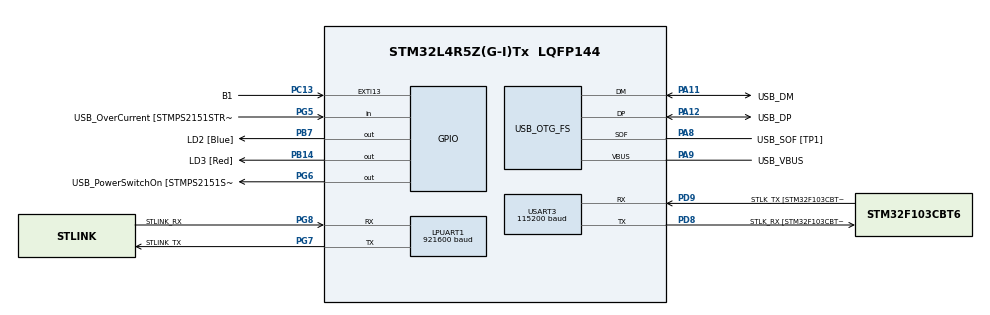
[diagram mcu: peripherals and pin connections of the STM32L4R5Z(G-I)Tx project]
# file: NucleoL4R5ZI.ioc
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Dma.LPUART1_RX.0.Direction=DMA_PERIPH_TO_MEMORY
Dma.LPUART1_RX.0.EventEnable=DISABLE
Dma.LPUART1_RX.0.Instance=DMA1_Channel1
Dma.LPUART1_RX.0.MemDataAlignment=DMA_MDATAALIGN_BYTE
Dma.LPUART1_RX.0.MemInc=DMA_MINC_ENABLE
Dma.LPUART1_RX.0.Mode=DMA_NORMAL
Dma.LPUART1_RX.0.PeriphDataAlignment=DMA_PDATAALIGN_BYTE
Dma.LPUART1_RX.0.PeriphInc=DMA_PINC_DISABLE
Dma.LPUART1_RX.0.Polarity=HAL_DMAMUX_REQUEST_GEN_RISING
Dma.LPUART1_RX.0.Priority=DMA_PRIORITY_MEDIUM
Dma.LPUART1_RX.0.RequestNumber=1
Dma.LPUART1_RX.0.SignalID=NONE
Dma.LPUART1_RX.0.SyncEnable=DISABLE
Dma.LPUART1_RX.0.SyncPolarity=HAL_DMAMUX_SYNC_NO_EVENT
Dma.LPUART1_RX.0.SyncRequestNumber=1
Dma.LPUART1_RX.0.SyncSignalID=NONE
Dma.Request0=LPUART1_RX
LPUART1.BaudRate=921600
LPUART1.OneBitSampling=UART_ONE_BIT_SAMPLE_DISABLE
LPUART1.WordLength=UART_WORDLENGTH_8B
Mcu.Family=STM32L4
Mcu.Name=STM32L4R5Z(G-I)Tx
Mcu.Package=LQFP144
NVIC.DMA1_Channel1_IRQn=true\:0\:0\:false\:false\:true\:false\:true\:true
NVIC.LPUART1_IRQn=true\:0\:0\:false\:false\:true\:true\:true\:true
NVIC.PriorityGroup=NVIC_PRIORITYGROUP_4
PA10.GPIO_Label=USB_ID
PA10.Signal=USB_OTG_FS_ID
PA11.GPIO_Label=USB_DM
PA11.Mode=Device_Only
PA11.Signal=USB_OTG_FS_DM
PA12.GPIO_Label=USB_DP
PA12.Mode=Device_Only
PA12.Signal=USB_OTG_FS_DP
PA13\ (JTMS/SWDIO).GPIO_Label=TMS
PA13\ (JTMS/SWDIO).Mode=Trace_Asynchronous_SW
PA13\ (JTMS/SWDIO).Signal=SYS_JTMS-SWDIO
PA14\ (JTCK/SWCLK).GPIO_Label=TCK
PA14\ (JTCK/SWCLK).Mode=Trace_Asynchronous_SW
PA14\ (JTCK/SWCLK).Signal=SYS_JTCK-SWCLK
PA8.GPIO_Label=USB_SOF [TP1]
PA8.Mode=Activate_SOF_FS
PA8.Signal=USB_OTG_FS_SOF
PA9.GPIO_Label=USB_VBUS
PA9.Mode=Activate_VBUS
PA9.Signal=USB_OTG_FS_VBUS
PB14.GPIO_Label=LD3 [Red]
PB14.Signal=GPIO_Output
PB3\ (JTDO/TRACESWO).GPIO_Label=SWO
PB3\ (JTDO/TRACESWO).Mode=Trace_Asynchronous_SW
PB3\ (JTDO/TRACESWO).Signal=SYS_JTDO-SWO
PB7.GPIO_Label=LD2 [Blue]
PB7.Signal=GPIO_Output
PC13.GPIO_Label=B1
PC13.Signal=GPXTI13
PC14-OSC32_IN\ (PC14).Mode=LSE-External-Oscillator
PC14-OSC32_IN\ (PC14).Signal=RCC_OSC32_IN
PC15-OSC32_OUT\ (PC15).Mode=LSE-External-Oscillator
PC15-OSC32_OUT\ (PC15).Signal=RCC_OSC32_OUT
PD8.GPIO_Label=STLK_RX [STM32F103CBT6_PA3]
PD8.Mode=Asynchronous
PD8.Signal=USART3_TX
PD9.GPIO_Label=STLK_TX [STM32F103CBT6_PA2]
PD9.Mode=Asynchronous
PD9.Signal=USART3_RX
PG5.GPIO_Label=USB_OverCurrent [STMPS2151STR_FAULT]
PG5.Signal=GPIO_Input
PG6.GPIO_Label=USB_PowerSwitchOn [STMPS2151STR_EN]
PG6.Signal=GPIO_Output
PG7.GPIO_Label=STLINK_TX
PG7.Mode=Asynchronous
PG7.Signal=LPUART1_TX
PG8.GPIO_Label=STLINK_RX
PG8.Mode=Asynchronous
PG8.Signal=LPUART1_RX
PH0-OSC_IN\ (PH0).Signal=RCC_OSC_IN
PH1-OSC_OUT\ (PH1).Signal=RCC_OSC_OUT
ProjectManager.HeapSize=0x200
ProjectManager.StackSize=0x400
ProjectManager.TargetToolchain=Makefile
RCC.48MHZClocksFreq_Value=24000000
RCC.ADCFreq_Value=96000000
RCC.AHBFreq_Value=120000000
RCC.APB1CLKDivider=RCC_HCLK_DIV2
RCC.APB1Freq_Value=60000000
RCC.APB1TimFreq_Value=120000000
RCC.APB2Freq_Value=120000000
RCC.APB2TimFreq_Value=120000000
RCC.CK48CLockSelection=RCC_USBCLKSOURCE_HSI48
RCC.CortexFreq_Value=120000000
RCC.HCLKFreq_Value=120000000
RCC.HSE_VALUE=8000000
RCC.HSI48_VALUE=48000000
RCC.HSI_VALUE=16000000
RCC.MSI_VALUE=4000000
RCC.PLLM1=2
RCC.PLLMUL=RCC_PLL_MUL9
RCC.PLLN=30
RCC.PLLSAI1N=12
RCC.PLLSourceVirtual=RCC_PLLSOURCE_HSI
RCC.PRESCALERUSB=RCC_USBCLKSOURCE_PLL_DIV1_5
RCC.SYSCLKFreq_VALUE=120000000
RCC.SYSCLKSource=RCC_SYSCLKSOURCE_PLLCLK
RCC.SYSCLKSourceVirtual=RCC_SYSCLKSOURCE_PLLCLK
RCC.USBFreq_Value=48000000
RCC.VCOOutputFreq_Value=240000000
USART3.BaudRate=115200
USART3.VirtualMode-Asynchronous=VM_ASYNC
USB_OTG_FS.VirtualMode=Device_Only
board=NUCLEO-L4R5ZI

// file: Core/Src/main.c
/* USER CODE BEGIN Header */
/**
  ******************************************************************************
  * @file           : main.c
  * @brief          : Main program body
  ******************************************************************************
  * @attention
  *
  * Copyright (c) 2026 STMicroelectronics.
  * All rights reserved.
  *
  * This software is licensed under terms that can be found in the LICENSE file
  * in the root directory of this software component.
  * If no LICENSE file comes with this software, it is provided AS-IS.
  *
  ******************************************************************************
  */
/* USER CODE END Header */
#include "main.h"

/* USER CODE BEGIN Includes */
#include <stdint.h>
#include <stdio.h>

#include "NeuralNetwork.h"
/* USER CODE END Includes */

/* USER CODE BEGIN PD */
#define MAX_READ_SIZE 16384 // Absolute max is 65535 due to HAL_UART_Receive_DMA size being uint16_t
/* USER CODE END PD */

UART_HandleTypeDef hlpuart1;
UART_HandleTypeDef huart3;
DMA_HandleTypeDef hdma_lpuart1_rx;

PCD_HandleTypeDef hpcd_USB_OTG_FS;

/* USER CODE BEGIN PV */
volatile static char receive_buff[MAX_READ_SIZE] = {'\0'};                //Define the receive array
volatile uint16_t receive_buff_cnt = 0;
static char send_msg[32] = "READY\r\n";
/* USER CODE END PV */

void SystemClock_Config(void);
static void MX_GPIO_Init(void);
static void MX_DMA_Init(void);
static void MX_LPUART1_UART_Init(void);
static void MX_USART3_UART_Init(void);
static void MX_USB_OTG_FS_PCD_Init(void);

/* USER CODE BEGIN 0 */
void RxEventCallback(UART_HandleTypeDef *huart, uint16_t Pos) {
  if(huart->Instance == LPUART1) { //Determine whether it is serial port 2
    uint16_t max_read = MAX_READ_SIZE - receive_buff_cnt;

    //Calculate the length of the received data
    //uint16_t data_length  = max_read - __HAL_DMA_GET_COUNTER(&hdma_usart2_rx);
    uint16_t data_length = Pos;

    receive_buff_cnt += data_length;

    if (receive_buff[receive_buff_cnt - 1] != '\n') {
      max_read -= data_length;
      //Restart to start DMA transmission of MAX_READ_SIZE bytes of data at a time
      HAL_UARTEx_ReceiveToIdle_DMA(&hlpuart1, (uint8_t*)(receive_buff + receive_buff_cnt), max_read);
    }
  }
}

/**
  * @brief  Function called to read the current micro second
  * @param  None
  * @retval None
  */
uint32_t getCurrentMicros(void)
{
  uint32_t m0 = HAL_GetTick();
  __IO uint32_t u0 = SysTick->VAL;
  uint32_t m1 = HAL_GetTick();
  __IO uint32_t u1 = SysTick->VAL;
  const uint32_t tms = SysTick->LOAD + 1;

  if (m1 != m0) {
    return (m1 * 1000 + ((tms - u1) * 1000) / tms);
  } else {
    return (m0 * 1000 + ((tms - u0) * 1000) / tms);
  }
}
/* USER CODE END 0 */

int main(void)
{

  /* MCU Configuration--------------------------------------------------------*/

  /* Reset of all peripherals, Initializes the Flash interface and the Systick. */
  HAL_Init();

  /* Configure the system clock */
  SystemClock_Config();

  /* Initialize all configured peripherals */
  MX_GPIO_Init();
  MX_DMA_Init();
  MX_LPUART1_UART_Init();
  MX_USART3_UART_Init();
  MX_USB_OTG_FS_PCD_Init();
  /* USER CODE BEGIN 2 */
  HAL_UART_RegisterRxEventCallback(&hlpuart1, RxEventCallback);
  HAL_UARTEx_ReceiveToIdle_DMA(&hlpuart1, (uint8_t*)receive_buff, MAX_READ_SIZE);
  HAL_UART_Transmit(&hlpuart1, (unsigned char *)send_msg, 7, 0x200); // Send READY
  /* USER CODE END 2 */

  /* Infinite loop */
  /* USER CODE BEGIN WHILE */
  while (1)
  {
    if (receive_buff_cnt > 0 && receive_buff[receive_buff_cnt - 1] == '\n') {
      float *inputs = serialBufToFloats(receive_buff, receive_buff_cnt);
      size_t len = snprintf(send_msg, 32, "%d\r\n", receive_buff_cnt);
      receive_buff_cnt = 0;
      HAL_UARTEx_ReceiveToIdle_DMA(&hlpuart1, (uint8_t*)receive_buff, MAX_READ_SIZE);

      HAL_UART_Transmit(&hlpuart1, (unsigned char *)send_msg, len, 0x200);

      uint32_t start = getCurrentMicros();
      struct NNResult res = neuralNetworkInfer(inputs);
      uint32_t stop = getCurrentMicros();

      len = snprintf(send_msg, 32, "%d,%d,%f,%lu\r\n", res.inference_count, res.label, (double)res.dist, stop - start);
      HAL_UART_Transmit(&hlpuart1, (unsigned char *)send_msg, len, 0x200);
    }
    /* USER CODE END WHILE */

  }
}

void SystemClock_Config(void)
{
  RCC_OscInitTypeDef RCC_OscInitStruct = {0};
  RCC_ClkInitTypeDef RCC_ClkInitStruct = {0};

  /** Configure the main internal regulator output voltage
  */
#ifdef CORE_CLOCK_48MHZ
  if (HAL_PWREx_ControlVoltageScaling(PWR_REGULATOR_VOLTAGE_SCALE1) != HAL_OK)
#else
  if (HAL_PWREx_ControlVoltageScaling(PWR_REGULATOR_VOLTAGE_SCALE1_BOOST) != HAL_OK)
#endif
  {
    Error_Handler();
  }

  /** Initializes the RCC Oscillators according to the specified parameters
  * in the RCC_OscInitTypeDef structure.
  */
  RCC_OscInitStruct.OscillatorType = RCC_OSCILLATORTYPE_HSI48|RCC_OSCILLATORTYPE_HSI;
  RCC_OscInitStruct.HSIState = RCC_HSI_ON;
  RCC_OscInitStruct.HSI48State = RCC_HSI48_ON;
  RCC_OscInitStruct.HSICalibrationValue = RCC_HSICALIBRATION_DEFAULT;
  RCC_OscInitStruct.PLL.PLLState = RCC_PLL_ON;
  RCC_OscInitStruct.PLL.PLLSource = RCC_PLLSOURCE_HSI;
#ifdef CORE_CLOCK_48MHZ
  RCC_OscInitStruct.PLL.PLLM = 1;
  RCC_OscInitStruct.PLL.PLLN = 12;
#else
  RCC_OscInitStruct.PLL.PLLM = 2;
  RCC_OscInitStruct.PLL.PLLN = 30;
#endif
  RCC_OscInitStruct.PLL.PLLP = RCC_PLLP_DIV2;
  RCC_OscInitStruct.PLL.PLLQ = RCC_PLLQ_DIV2;
  RCC_OscInitStruct.PLL.PLLR = RCC_PLLR_DIV2;
  if (HAL_RCC_OscConfig(&RCC_OscInitStruct) != HAL_OK)
  {
    Error_Handler();
  }

  /** Initializes the CPU, AHB and APB buses clocks
  */
  RCC_ClkInitStruct.ClockType = RCC_CLOCKTYPE_HCLK|RCC_CLOCKTYPE_SYSCLK
                              |RCC_CLOCKTYPE_PCLK1|RCC_CLOCKTYPE_PCLK2;
  RCC_ClkInitStruct.SYSCLKSource = RCC_SYSCLKSOURCE_PLLCLK;
#ifdef CORE_CLOCK_48MHZ
  RCC_ClkInitStruct.AHBCLKDivider = RCC_SYSCLK_DIV2;
#else
  RCC_ClkInitStruct.AHBCLKDivider = RCC_SYSCLK_DIV1;
#endif
  RCC_ClkInitStruct.APB1CLKDivider = RCC_HCLK_DIV2;
  RCC_ClkInitStruct.APB2CLKDivider = RCC_HCLK_DIV1;

#ifdef CORE_CLOCK_48MHZ
  if (HAL_RCC_ClockConfig(&RCC_ClkInitStruct, FLASH_LATENCY_2) != HAL_OK)
#else
  if (HAL_RCC_ClockConfig(&RCC_ClkInitStruct, FLASH_LATENCY_5) != HAL_OK)
#endif
  {
    Error_Handler();
  }
}

static void MX_LPUART1_UART_Init(void)
{

  hlpuart1.Instance = LPUART1;
  hlpuart1.Init.BaudRate = 921600;
  hlpuart1.Init.WordLength = UART_WORDLENGTH_8B;
  hlpuart1.Init.StopBits = UART_STOPBITS_1;
  hlpuart1.Init.Parity = UART_PARITY_NONE;
  hlpuart1.Init.Mode = UART_MODE_TX_RX;
  hlpuart1.Init.HwFlowCtl = UART_HWCONTROL_NONE;
  hlpuart1.Init.OneBitSampling = UART_ONE_BIT_SAMPLE_DISABLE;
  hlpuart1.Init.ClockPrescaler = UART_PRESCALER_DIV1;
  hlpuart1.AdvancedInit.AdvFeatureInit = UART_ADVFEATURE_NO_INIT;
  hlpuart1.FifoMode = UART_FIFOMODE_DISABLE;
  if (HAL_UART_Init(&hlpuart1) != HAL_OK)
  {
    Error_Handler();
  }
  if (HAL_UARTEx_SetTxFifoThreshold(&hlpuart1, UART_TXFIFO_THRESHOLD_1_8) != HAL_OK)
  {
    Error_Handler();
  }
  if (HAL_UARTEx_SetRxFifoThreshold(&hlpuart1, UART_RXFIFO_THRESHOLD_1_8) != HAL_OK)
  {
    Error_Handler();
  }
  if (HAL_UARTEx_DisableFifoMode(&hlpuart1) != HAL_OK)
  {
    Error_Handler();
  }

}

static void MX_USART3_UART_Init(void)
{

  huart3.Instance = USART3;
  huart3.Init.BaudRate = 115200;
  huart3.Init.WordLength = UART_WORDLENGTH_8B;
  huart3.Init.StopBits = UART_STOPBITS_1;
  huart3.Init.Parity = UART_PARITY_NONE;
  huart3.Init.Mode = UART_MODE_TX_RX;
  huart3.Init.HwFlowCtl = UART_HWCONTROL_NONE;
  huart3.Init.OverSampling = UART_OVERSAMPLING_16;
  huart3.Init.OneBitSampling = UART_ONE_BIT_SAMPLE_DISABLE;
  huart3.Init.ClockPrescaler = UART_PRESCALER_DIV1;
  huart3.AdvancedInit.AdvFeatureInit = UART_ADVFEATURE_NO_INIT;
  if (HAL_UART_Init(&huart3) != HAL_OK)
  {
    Error_Handler();
  }
  if (HAL_UARTEx_SetTxFifoThreshold(&huart3, UART_TXFIFO_THRESHOLD_1_8) != HAL_OK)
  {
    Error_Handler();
  }
  if (HAL_UARTEx_SetRxFifoThreshold(&huart3, UART_RXFIFO_THRESHOLD_1_8) != HAL_OK)
  {
    Error_Handler();
  }
  if (HAL_UARTEx_DisableFifoMode(&huart3) != HAL_OK)
  {
    Error_Handler();
  }

}

static void MX_USB_OTG_FS_PCD_Init(void)
{

  hpcd_USB_OTG_FS.Instance = USB_OTG_FS;
  hpcd_USB_OTG_FS.Init.dev_endpoints = 6;
  hpcd_USB_OTG_FS.Init.speed = PCD_SPEED_FULL;
  hpcd_USB_OTG_FS.Init.phy_itface = PCD_PHY_EMBEDDED;
  hpcd_USB_OTG_FS.Init.Sof_enable = ENABLE;
  hpcd_USB_OTG_FS.Init.low_power_enable = DISABLE;
  hpcd_USB_OTG_FS.Init.lpm_enable = DISABLE;
  hpcd_USB_OTG_FS.Init.battery_charging_enable = ENABLE;
  hpcd_USB_OTG_FS.Init.use_dedicated_ep1 = DISABLE;
  hpcd_USB_OTG_FS.Init.vbus_sensing_enable = ENABLE;
  if (HAL_PCD_Init(&hpcd_USB_OTG_FS) != HAL_OK)
  {
    Error_Handler();
  }

}

static void MX_DMA_Init(void)
{

  /* DMA controller clock enable */
  __HAL_RCC_DMAMUX1_CLK_ENABLE();
  __HAL_RCC_DMA1_CLK_ENABLE();

  /* DMA interrupt init */
  /* DMA1_Channel1_IRQn interrupt configuration */
  HAL_NVIC_SetPriority(DMA1_Channel1_IRQn, 0, 0);
  HAL_NVIC_EnableIRQ(DMA1_Channel1_IRQn);

}

static void MX_GPIO_Init(void)
{
  GPIO_InitTypeDef GPIO_InitStruct = {0};

  /* GPIO Ports Clock Enable */
  __HAL_RCC_GPIOC_CLK_ENABLE();
  __HAL_RCC_GPIOH_CLK_ENABLE();
  __HAL_RCC_GPIOB_CLK_ENABLE();
  __HAL_RCC_GPIOD_CLK_ENABLE();
  __HAL_RCC_GPIOG_CLK_ENABLE();
  HAL_PWREx_EnableVddIO2();
  __HAL_RCC_GPIOA_CLK_ENABLE();

  /*Configure GPIO pin Output Level */
  HAL_GPIO_WritePin(GPIOB, LD3_Pin|LD2_Pin, GPIO_PIN_RESET);

  /*Configure GPIO pin Output Level */
  HAL_GPIO_WritePin(USB_PowerSwitchOn_GPIO_Port, USB_PowerSwitchOn_Pin, GPIO_PIN_RESET);

  /*Configure GPIO pin : B1_Pin */
  GPIO_InitStruct.Pin = B1_Pin;
  GPIO_InitStruct.Mode = GPIO_MODE_IT_RISING;
  GPIO_InitStruct.Pull = GPIO_NOPULL;
  HAL_GPIO_Init(B1_GPIO_Port, &GPIO_InitStruct);

  /*Configure GPIO pins : LD3_Pin LD2_Pin */
  GPIO_InitStruct.Pin = LD3_Pin|LD2_Pin;
  GPIO_InitStruct.Mode = GPIO_MODE_OUTPUT_PP;
  GPIO_InitStruct.Pull = GPIO_NOPULL;
  GPIO_InitStruct.Speed = GPIO_SPEED_FREQ_LOW;
  HAL_GPIO_Init(GPIOB, &GPIO_InitStruct);

  /*Configure GPIO pin : USB_OverCurrent_Pin */
  GPIO_InitStruct.Pin = USB_OverCurrent_Pin;
  GPIO_InitStruct.Mode = GPIO_MODE_INPUT;
  GPIO_InitStruct.Pull = GPIO_NOPULL;
  HAL_GPIO_Init(USB_OverCurrent_GPIO_Port, &GPIO_InitStruct);

  /*Configure GPIO pin : USB_PowerSwitchOn_Pin */
  GPIO_InitStruct.Pin = USB_PowerSwitchOn_Pin;
  GPIO_InitStruct.Mode = GPIO_MODE_OUTPUT_PP;
  GPIO_InitStruct.Pull = GPIO_NOPULL;
  GPIO_InitStruct.Speed = GPIO_SPEED_FREQ_LOW;
  HAL_GPIO_Init(USB_PowerSwitchOn_GPIO_Port, &GPIO_InitStruct);

}

void Error_Handler(void)
{
  __disable_irq();
  while (1)
  {
  }
}
